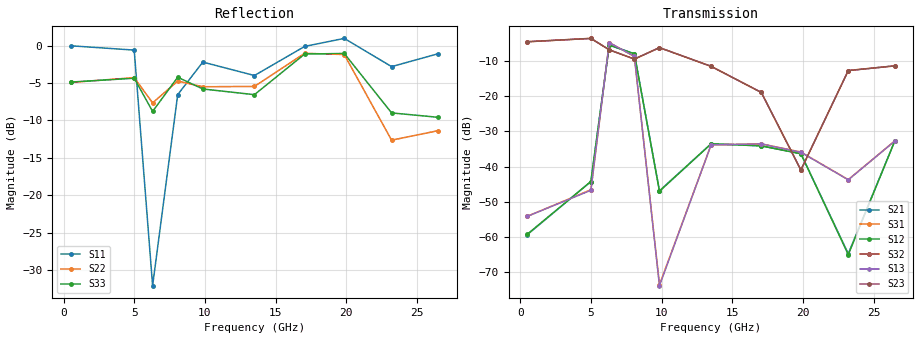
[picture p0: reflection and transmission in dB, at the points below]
! Mini-Circuits
! BBFCG2-672+
! Reference Information: Unit 10, Test Board, eCal w/ Auto Port Extension & Match Correction
! Temperature: +125 Degrees Celsius
# Hz S  dB  R 50
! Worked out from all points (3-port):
!   891 points, 500 MHz to 26.5 GHz, reference 50 ohm
!   strongest paths, dB at 500 MHz, 2.72 GHz, 6.6 GHz, 15.4 GHz, 26.5 GHz:
!     S32: -4.6, -9.1, -7.2, -25.1, -11.4
!     S31: -54.1, -35.2, -4.7, -34.0, -32.7
!     S21: -59.4, -48.1, -5.2, -33.2, -32.7
!   lowest |S11| = -32.1 dB at 6.3 GHz (marker M1), VSWR 1.05, Z = 50 - j2.48 ohm
!   |S11| at or under -10 dB: 6.05 GHz to 7.643 GHz (1.592 GHz wide, 23.3 % of centre); 17.66 GHz to 17.96 GHz (302 MHz wide, 1.7 % of centre)
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5e8  -0.02 179.0  -59.23 -139.7  -54.15 109.5
     -59.35 -140.4  -4.93 -150.8  -4.61 -31.4
     -54.13 109.3  -4.61 -31.4  -4.88 -151.1
5e9  -0.60 114.8  -44.26 25.9  -46.75 103.1
     -44.28 25.7  -4.28 134.8  -3.65 -147.2
     -46.60 103.1  -3.66 -147.2  -4.36 120.4
6.3e9  -32.11 -88.7  -5.57 -112.6  -4.85 71.1
       -5.56 -112.8  -7.66 156.7  -6.90 152.4
       -4.85 71.0  -6.90 152.5  -8.80 167.8
8.075e9  -6.56 49.1  -8.03 -58.8  -8.79 108.3
         -8.02 -59.0  -4.75 93.9  -9.53 124.5
         -8.78 108.2  -9.53 124.6  -4.23 69.7
9.85e9  -2.20 -20.8  -47.02 -95.9  -73.81 37.3
        -46.88 -96.2  -5.50 44.6  -6.28 115.7
        -73.53 42.2  -6.28 115.8  -5.80 4.2
1.35e10  -4.00 -23.9  -33.56 -156.3  -33.87 -162.1
         -33.57 -156.5  -5.46 41.1  -11.58 128.9
         -33.87 -162.3  -11.59 129.1  -6.56 16.1
1.705e10  -0.11 -24.2  -34.15 -161.7  -33.58 -162.5
          -34.13 -162.1  -1.03 21.1  -18.99 144.3
          -33.58 -162.6  -18.99 144.5  -1.13 14.3
1.985e10  0.97 -152.5  -36.38 81.4  -35.97 84.6
          -36.37 80.7  -1.19 -113.2  -40.98 156.9
          -35.90 84.6  -41.02 157.1  -1.05 -123.6
2.32e10  -2.81 -140.2  -64.99 153.4  -43.78 -153.3
         -64.73 154.3  -12.65 60.9  -12.78 -33.1
         -43.72 -154.1  -12.78 -32.7  -9.00 15.9
2.65e10  -1.08 95.8  -32.66 -42.5  -32.74 -46.5
         -32.65 -42.8  -11.37 90.1  -11.45 -93.3
         -32.71 -46.9  -11.44 -93.0  -9.59 88.3
